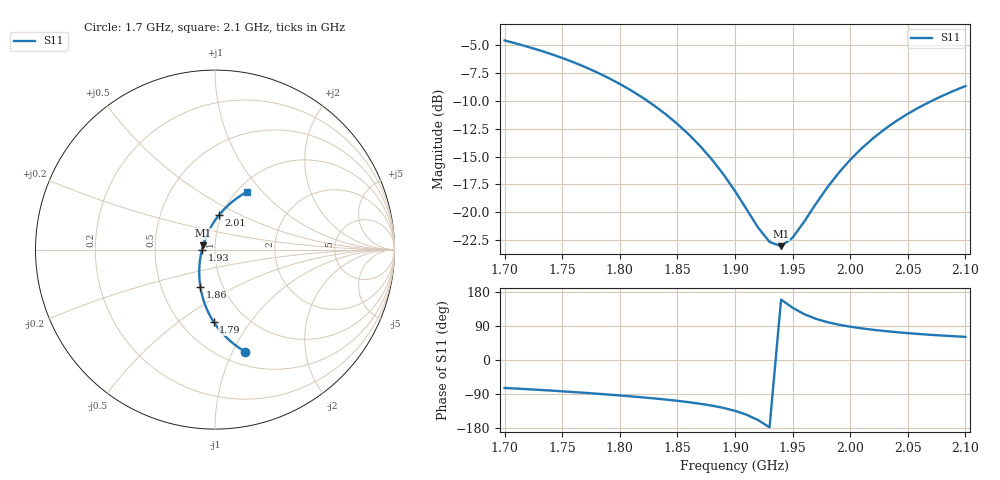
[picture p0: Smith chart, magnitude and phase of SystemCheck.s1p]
! Generated by circuitRF - EM: openEMS
! circuitRF-EM setup: SystemCheck Coarse
! circuitRF-EM layout: SystemCheck.c3d
! circuitRF-EM written: 2026-10-19 01:12:02Z
! circuitRF-EM geometry: 790b15e1bc67d256
! circuitRF-EM mesh: 570d45945de7818d
! circuitRF-EM ports: 84820064c771a764
! circuitRF-EM model: openEMS 0.37.0 (v0.37.0, CSXCAD v0.7.0)
! circuitRF-EM port 1: 'port/1' from 'armLo' to 'armHi', lumped, 50 Ohm
! circuitRF-EM 3D grid: 106 x 81 x 101 = 867186 cells; smallest cell 1.425 mm on y, set by 'armLo' edge at y = -1.9 mm (thirds rule, outside; local cell 1.425 mm, set by 'armLo'); 'armHi' edge at y = -1.9 mm (thirds rule, outside; local cell 1.425 mm, set by 'armLo'); 'armLo' edge at y = -1.9 mm (th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
! circuitRF-EM 3D openEMS run port 1: dt 3.39793E-12 s (estimate 3.34829E-12 s), 4029 steps, port signals unmeasured (stopped within the pulse) and energy 47.8 dB against 40 dB, stopped by openEMS's energy criterion, converged
! circuitRF-EM 3D dielectric loss fitted at: 1.9 GHz
! circuitRF-EM 3D perfect conductors: armLo, armHi
! circuitRF-EM 3D operating temperature: 20 C
! circuitRF-EM: re-running the EM setup rewrites this file. If circuitRF reports it as stale, the layout's cross-section changed after this file was written.
# GHz S RI R 50
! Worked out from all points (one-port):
!   41 points, 1.7 GHz to 2.1 GHz, reference 50 ohm
!   lowest |S11| = -23.0 dB at 1.94 GHz (marker M1), VSWR 1.15, Z = 43.8 + j2.17 ohm
!   |S11| at or under -10 dB: 1.824 GHz to 2.07 GHz (246.4 MHz wide, 12.7 % of centre)
!   S11 on the Smith chart (normalised r, x): 1.7 GHz: 0.64, -1.11; 1.79 GHz: 0.71, -0.68; 1.86 GHz: 0.78, -0.34; 1.93 GHz: 0.86, -0.01; 2.01 GHz: 0.97, +0.39; 2.1 GHz: 1.11, +0.83
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1.7  0.1652 -0.5683
1.73  0.1038 -0.5249
1.75  0.0636 -0.4896
1.77  0.0258 -0.4486
1.79  -0.00819 -0.4019
1.8  -0.0233 -0.3767
1.82  -0.0492 -0.3232
1.83  -0.0598 -0.2953
1.85  -0.0759 -0.2375
1.86  -0.0815 -0.2081
1.87  -0.0854 -0.1784
1.88  -0.0875 -0.1487
1.89  -0.088 -0.119
1.9  -0.0867 -0.0895
1.92  -0.0795 -0.0314
1.93  -0.0735 -0.00307
1.94  -0.066 0.0246
1.95  -0.057 0.0516
1.96  -0.0467 0.0777
1.98  -0.0223 0.1271
1.99  -0.00845 0.1501
2  0.00643 0.172
2.01  0.0222 0.1926
2.03  0.0556 0.2299
2.04  0.073 0.2465
2.06  0.1084 0.276
2.08  0.1437 0.3012
2.1  0.1785 0.3232
